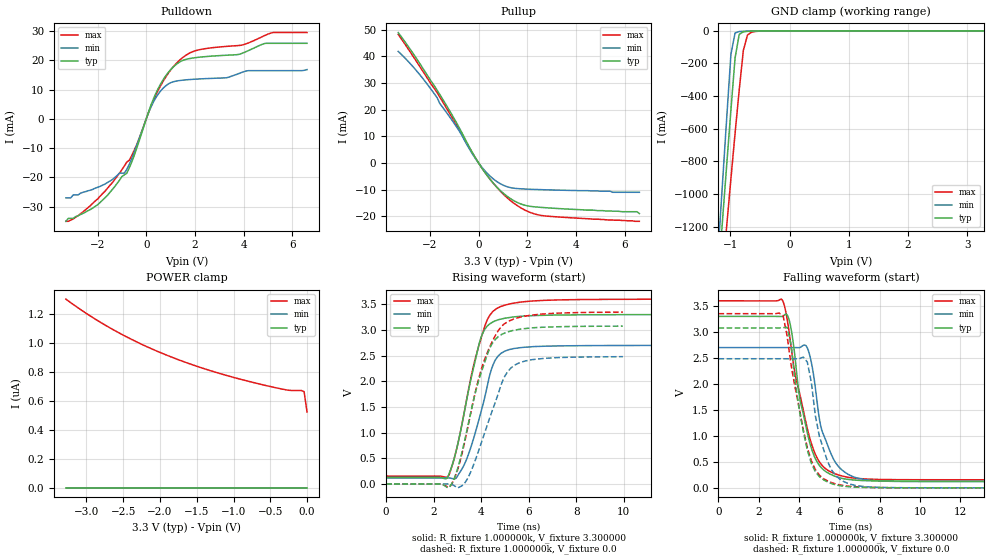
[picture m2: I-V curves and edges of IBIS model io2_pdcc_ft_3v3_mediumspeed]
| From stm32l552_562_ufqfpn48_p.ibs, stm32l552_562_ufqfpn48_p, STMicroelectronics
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|   Model io2_pdcc_ft_3v3_mediumspeed
[Model]  io2_pdcc_ft_3v3_mediumspeed
Model_type I/O
Polarity   Non-Inverting
Enable   Active-Low
Vinl =   0.990000V
Vinh =   2.310000V
Vmeas =  1.650000V
Cref =   40.000000pF
Rref =   100.000000M
Vref =   0.0V
C_comp   4.843300pF   4.282700pF   5.299100pF
[Temperature Range]   25.000000   -40.000000   0.125000k
[Pullup Reference]   3.300000V   2.700000V   3.600000V
[Pulldown Reference]   0.0V   0.0V   0.0V
[POWER Clamp Reference]   3.300000V   2.700000V   3.600000V
[GND Clamp Reference]   0.0V   0.0V   0.0V
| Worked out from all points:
|   slope of the pulldown table from 0 to 0.495 V, typ, clamps not added: 47.5 ohm
|   slope of the pullup table from 0 to 0.495 V, typ, clamps not added: 77.3 ohm
|   GND clamp passes 1 mA (typ) near -0.58 V on its own axis
|   rising waveform, R_fixture 1.000000k, V_fixture 3.300000: 20-80 % time 874ps typ, 892ps min, 997ps max; typ from 0.128 V to 3.3 V
|   rising waveform, R_fixture 1.000000k, V_fixture 0.0: 20-80 % time 1.03ns typ, 1.11ns min, 1.14ns max; typ from 0 V to 3.07 V
|   falling waveform, R_fixture 1.000000k, V_fixture 3.300000: 20-80 % time 859ps typ, 894ps min, 1.08ns max; typ from 3.3 V to 0.128 V
|   falling waveform, R_fixture 1.000000k, V_fixture 0.0: 20-80 % time 807ps typ, 805ps min, 998ps max; typ from 3.08 V to 0 V
[Pulldown]
|Voltage   I(typ)   I(min)   I(max)
-3.3V     -35mA      -27mA      -35mA
-2V       -29.4mA    -23.4mA    -27.4mA
-800mV    -18.58mA   -17.27mA   -14.77mA
-400mV    -10.26mA   -9.232mA   -8.958mA
100mV     2.513mA    2.208mA    2.267mA
400mV     8.782mA    7.287mA    8.184mA
800mV     14.68mA    11.26mA    14.27mA
1.3V      19.02mA    12.98mA    19.48mA
2V        20.86mA    13.52mA    23.19mA
3.9V      22.24mA    15.76mA    25.13mA
5.2V      25.78mA    16.44mA    29.44mA
6.6V      25.78mA    16.8mA     29.44mA
[Pullup]
|Voltage   I(typ)   I(min)   I(max)
-3.3V     48.98mA    41.91mA    48.31mA
-2.6V     39.91mA    35.19mA    38.84mA
-1.9V     30.08mA    27.03mA    29mA
-1.6V     25.82mA    22.46mA    24.9mA
-1.1V     18.19mA    16.17mA    17.21mA
100mV     -1.429mA   -1.206mA   -1.392mA
600mV     -7.545mA   -5.957mA   -7.567mA
1.2V      -12.7mA    -9.001mA   -13.28mA
1.8V      -15.6mA    -9.729mA   -17.2mA
2.5V      -16.63mA   -9.994mA   -19.58mA
6.5V      -18.3mA    -11mA      -21.9mA
6.6V      -19mA      -11mA      -21.9mA
[GND_clamp]
|Voltage   I(typ)   I(min)   I(max)
-3.3V     -9.767A    -9.748A    -9.881A
-1.2V     -1.489A    -1.316A    -1.768A
-1.13V    -1.15A     -919.7mA   -1.477A
-1.06V    -814.4mA   -527.2mA   -1.189A
-990mV    -484.1mA   -143.5mA   -905.3mA
-920mV    -166.2mA   -12.77mA   -627.6mA
-850mV    -21.87mA   -4.511mA   -362mA
-780mV    -5.991mA   -2.83mA    -119.7mA
-710mV    -3.238mA   -1.563mA   -25.44mA
-640mV    -1.838mA   -627.8uA   -8.016mA
-290mV    -1.61uA    0A         -104.4uA
3.28V     0A         0A         431.1nA
[POWER_clamp]
|Voltage   I(typ)   I(min)   I(max)
-3.28V    0A         0A         1.304uA
-2.96V    0A         0A         1.191uA
-2.6V     0A         0A         1.083uA
-2.24V    0A         0A         989.7nA
-1.84V    0A         0A         902.9nA
-1.4V     0A         0A         823.6nA
-880mV    0A         0A         747.1nA
-320mV    0A         0A         680.5nA
-240mV    0A         0A         673.6nA
-80mV     0A         0A         672.6nA
-40mV     0A         0A         665.5nA
0V        0A         0A         524.5nA
[Ramp]
| variable   typ   min   max
dV/dt_r  1.96650/1.13813n   1.60704/1.18468n   2.14475/1.25257n
dV/dt_f  1.97245/1.31685n   1.61310/1.32520n   2.15078/1.32548n
R_load = 10.000000k
[Rising Waveform]
R_fixture= 1.000000k
V_fixture= 3.300000
V_fixture_min= 2.700000
V_fixture_max= 3.600000
|time   V(typ)   V(min)   V(max)
0s        127.8mV    118.3mV    154.8mV
2.613ns   154mV      118.6mV    149.2mV
2.943ns   634.3mV    111.9mV    634.4mV
3.273ns   1.353V     362.4mV    1.359V
3.604ns   2.11V      767.6mV    2.143V
3.964ns   2.807V     1.35V      2.785V
4.264ns   3.077V     1.92V      3.201V
4.655ns   3.185V     2.452V     3.415V
6.246ns   3.278V     2.675V     3.564V
14.95ns   3.298V     2.698V     3.598V
[Rising Waveform]
R_fixture= 1.000000k
V_fixture= 0.0
V_fixture_min= 0.0
V_fixture_max= 0.0
|time   V(typ)   V(min)   V(max)
0s        35.26nV    22.58nV    11.62uV
2.723ns   -21.66mV   -3.899mV   -29.15mV
3.063ns   385.8mV    -65.05mV   359.4mV
3.483ns   1.221V     156.6mV    1.202V
3.964ns   2.114V     742.1mV    2.163V
4.324ns   2.597V     1.237V     2.63V
4.965ns   2.932V     2.068V     3.112V
5.405ns   2.994V     2.312V     3.216V
6.166ns   3.04V      2.422V     3.288V
9.97ns    3.073V     2.478V     3.345V
[Falling Waveform]
R_fixture= 1.000000k
V_fixture= 3.300000
V_fixture_min= 2.700000
V_fixture_max= 3.600000
|time   V(typ)   V(min)   V(max)
0s        3.3V       2.7V       3.6V
3.123ns   3.298V     2.7V       3.63V
3.393ns   3.335V     2.7V       3.272V
3.784ns   2.553V     2.7V       2.221V
4.024ns   1.743V     2.7V       1.818V
4.414ns   1.044V     2.687V     1.127V
5.045ns   412.7mV    1.236V     477mV
5.405ns   292.7mV    827.2mV    341.8mV
7.177ns   139.9mV    163.9mV    174.4mV
14.95ns   128.3mV    118.8mV    155.5mV
[Falling Waveform]
R_fixture= 1.000000k
V_fixture= 0.0
V_fixture_min= 0.0
V_fixture_max= 0.0
|time   V(typ)   V(min)   V(max)
0s        3.078V     2.485V     3.352V
3.003ns   3.077V     2.485V     3.364V
3.203ns   3.084V     2.485V     3.316V
3.403ns   3.091V     2.485V     2.922V
4.204ns   1.091V     2.518V     1.118V
4.605ns   472.2mV    2.03V      520.5mV
5.005ns   215.8mV    989.6mV    245.2mV
5.405ns   114.1mV    511.4mV    134.1mV
6.607ns   17.73mV    63.73mV    26.08mV
99.7ns    6.467uV    6.352uV    20.66uV
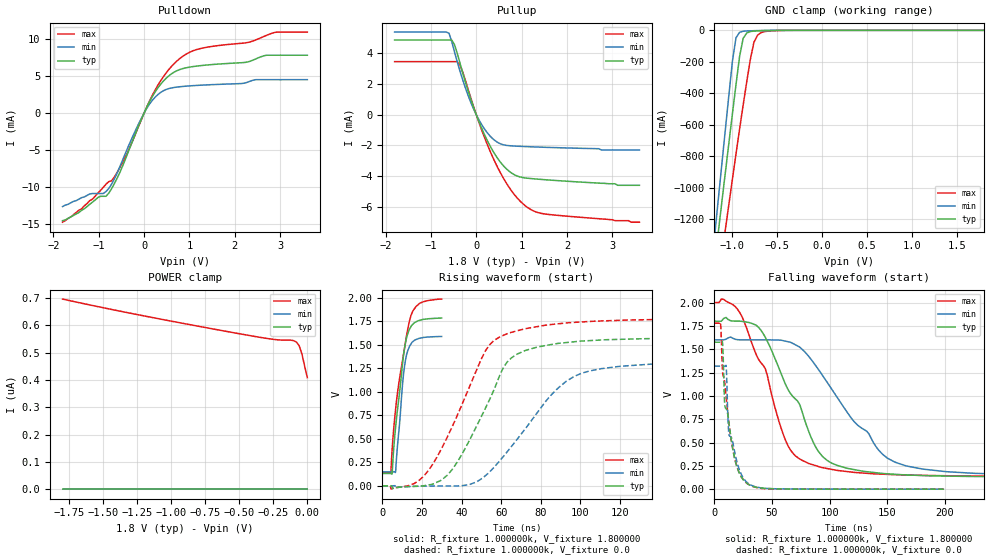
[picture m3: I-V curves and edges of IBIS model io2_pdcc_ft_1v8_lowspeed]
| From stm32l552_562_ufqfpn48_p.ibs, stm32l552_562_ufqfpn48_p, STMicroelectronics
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|   Model io2_pdcc_ft_1v8_lowspeed
[Model]  io2_pdcc_ft_1v8_lowspeed
Model_type I/O
Polarity   Non-Inverting
Enable   Active-Low
Vinl =   0.540000V
Vinh =   1.260000V
Vmeas =  0.900000V
Cref =   50.000000pF
Rref =   100.000000M
Vref =   0.0V
C_comp   4.366800pF   3.639100pF   5.105000pF
[Temperature Range]   25.000000   -40.000000   0.125000k
[Pullup Reference]   1.800000V   1.600000V   2.000000V
[Pulldown Reference]   0.0V   0.0V   0.0V
[POWER Clamp Reference]   1.800000V   1.600000V   2.000000V
[GND Clamp Reference]   0.0V   0.0V   0.0V
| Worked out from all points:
|   slope of the pulldown table from 0 to 0.27 V, typ, clamps not added: 87.5 ohm
|   slope of the pullup table from 0 to 0.27 V, typ, clamps not added: 147 ohm
|   GND clamp passes 1 mA (typ) near -0.58 V on its own axis
|   rising waveform, R_fixture 1.000000k, V_fixture 1.800000: 20-80 % time 5.14ns typ, 3.71ns min, 7.01ns max; typ from 0.131 V to 1.78 V
|   rising waveform, R_fixture 1.000000k, V_fixture 0.0: 20-80 % time 21.5ns typ, 30.3ns min, 22.8ns max; typ from 0 V to 1.57 V
|   falling waveform, R_fixture 1.000000k, V_fixture 1.800000: 20-80 % time 37ns typ, 52.6ns min, 31.5ns max; typ from 1.8 V to 0.131 V
|   falling waveform, R_fixture 1.000000k, V_fixture 0.0: 20-80 % time 9.82ns typ, 9.16ns min, 10.7ns max; typ from 1.57 V to 0 V
[Pulldown]
|Voltage   I(typ)   I(min)   I(max)
-1.8V     -14.5mA    -12.6mA    -14.7mA
-1.38V    -13.1mA    -11.4mA    -12.9mA
-900mV    -11.21mA   -10.84mA   -10mA
-780mV    -10.79mA   -10.16mA   -9.24mA
-480mV    -7.221mA   -6.409mA   -6.723mA
60mV      806.3uA    646.5uA    843.8uA
300mV     3.356mA    2.463mA    3.703mA
600mV     5.259mA    3.369mA    6.249mA
1.2V      6.348mA    3.729mA    8.613mA
2.28V     6.866mA    4.147mA    9.489mA
2.88V     7.779mA    4.489mA    10.85mA
3.6V      7.779mA    4.489mA    10.9mA
[Pullup]
|Voltage   I(typ)   I(min)   I(max)
-1.8V     4.843mA    5.363mA    3.44mA
-600mV    4.843mA    5.291mA    3.44mA
-540mV    4.843mA    4.745mA    3.44mA
-420mV    4.004mA    3.449mA    3.44mA
-300mV    2.736mA    2.275mA    2.784mA
-120mV    1.005mA    795.6uA    1.088mA
180mV     -1.289mA   -926.4uA   -1.468mA
480mV     -2.883mA   -1.823mA   -3.482mA
840mV     -3.912mA   -2.048mA   -5.199mA
1.14V     -4.143mA   -2.089mA   -6.059mA
1.44V     -4.22mA    -2.122mA   -6.431mA
3.6V      -4.6mA     -2.3mA     -7mA
[GND_clamp]
|Voltage   I(typ)   I(min)   I(max)
-1.8V     -4.43A     -4.747A    -4.297A
-1.2V     -1.489A    -1.316A    -1.768A
-1.16V    -1.295A    -1.089A    -1.601A
-1.12V    -1.102A    -863.2mA   -1.436A
-1.08V    -909.8mA   -638.7mA   -1.271A
-1V       -530.7mA   -197.2mA   -945.5mA
-960mV    -345.6mA   -47.17mA   -785.2mA
-920mV    -166mA     -12.66mA   -627.5mA
-880mV    -50.53mA   -5.875mA   -473.7mA
-760mV    -4.783mA   -2.396mA   -75.32mA
-680mV    -2.529mA   -1.097mA   -14.51mA
1.8V      0A         0A         305.1nA
[POWER_clamp]
|Voltage   I(typ)   I(min)   I(max)
-1.8V     0A         0A         696.8nA
-1.22V    0A         0A         637nA
-520mV    0A         0A         571.6nA
-260mV    0A         0A         549.8nA
-200mV    0A         0A         546.8nA
-120mV    0A         0A         546.1nA
-100mV    0A         0A         544.2nA
-80mV     0A         0A         539.2nA
-60mV     0A         0A         525.8nA
-40mV     0A         0A         495.9nA
-20mV     0A         0A         451.3nA
0V        0A         0A         408.6nA
[Ramp]
| variable   typ   min   max
dV/dt_r  1.06626/11.69097n   0.94386/12.69962n   1.18619/13.17653n
dV/dt_f  1.07230/25.60331n   0.95160/34.23696n   1.19173/22.45042n
R_load = 10.000000k
[Rising Waveform]
R_fixture= 1.000000k
V_fixture= 1.800000
V_fixture_min= 1.600000
V_fixture_max= 2.000000
|time   V(typ)   V(min)   V(max)
0s        131mV      148.5mV    138.1mV
4.264ns   131mV      148.5mV    139.8mV
4.985ns   142.4mV    148.6mV    398.4mV
6.667ns   619mV      147.5mV    811.3mV
9.91ns    1.245V     1.01V      1.3V
11.05ns   1.444V     1.252V     1.446V
12.37ns   1.588V     1.406V     1.618V
14.47ns   1.696V     1.51V      1.815V
18.86ns   1.761V     1.57V      1.942V
29.91ns   1.785V     1.589V     1.987V
[Rising Waveform]
R_fixture= 1.000000k
V_fixture= 0.0
V_fixture_min= 0.0
V_fixture_max= 0.0
|time   V(typ)   V(min)   V(max)
0s        30.16nV    26.35nV    13.38uV
18.42ns   -4.144mV   -4.632mV   55.4mV
25.23ns   15.91mV    -2.946mV   223mV
32.83ns   113.3mV    -2.022mV   520.3mV
52.05ns   826.4mV    107.9mV    1.437V
63.66ns   1.33V      378.3mV    1.624V
85.29ns   1.503V     967.4mV    1.716V
100.5ns   1.54V      1.197V     1.744V
135.3ns   1.566V     1.294V     1.768V
199.4ns   1.574V     1.316V     1.777V
[Falling Waveform]
R_fixture= 1.000000k
V_fixture= 1.800000
V_fixture_min= 1.600000
V_fixture_max= 2.000000
|time   V(typ)   V(min)   V(max)
0s        1.8V       1.6V       2V
20.02ns   1.8V       1.602V     1.928V
40.04ns   1.709V     1.6V       1.36V
66.07ns   1.024V     1.574V     419.2mV
74.07ns   906.4mV    1.522V     322.9mV
90.09ns   407mV      1.286V     243.6mV
106.1ns   256.9mV    992.5mV    201.9mV
150.2ns   164.7mV    332.3mV    158.5mV
202.2ns   140.2mV    186.8mV    143.8mV
997ns     131mV      148.5mV    138.1mV
[Falling Waveform]
R_fixture= 1.000000k
V_fixture= 0.0
V_fixture_min= 0.0
V_fixture_max= 0.0
|time   V(typ)   V(min)   V(max)
0s        1.575V     1.319V     1.778V
5.205ns   1.575V     1.319V     1.79V
6.807ns   1.587V     1.319V     1.301V
7.608ns   1.42V      1.319V     1.214V
8.809ns   925mV      1.319V     1.151V
10.01ns   864.1mV    1.327V     1.008V
12.41ns   724mV      598.6mV    726.9mV
18.82ns   265.8mV    327.6mV    271.9mV
28.43ns   61.73mV    71.22mV    59.55mV
199.4ns   19.37uV    39.34uV    31.94uV
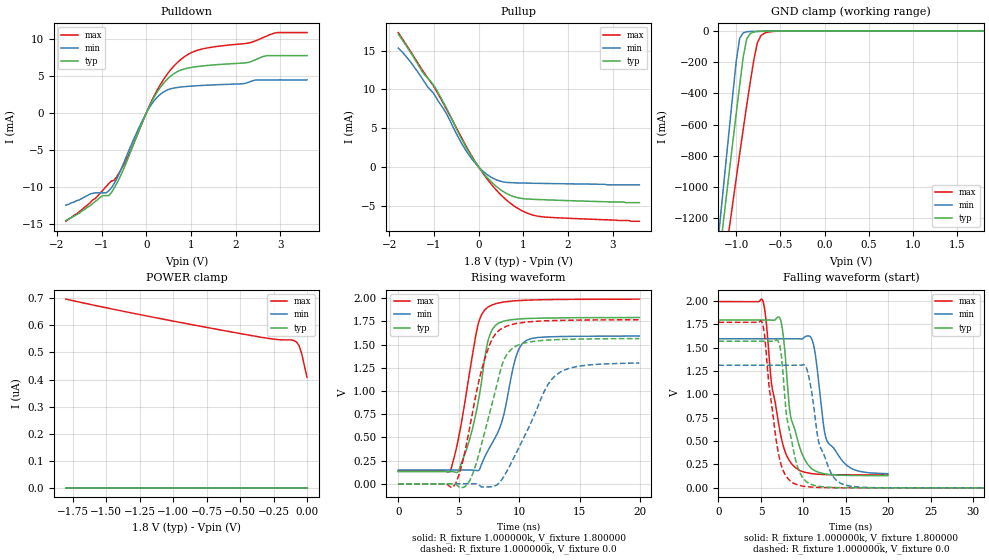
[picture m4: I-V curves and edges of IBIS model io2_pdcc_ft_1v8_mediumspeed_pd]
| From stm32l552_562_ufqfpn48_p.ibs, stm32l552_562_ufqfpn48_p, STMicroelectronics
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|   Model io2_pdcc_ft_1v8_mediumspeed_pd
[Model]  io2_pdcc_ft_1v8_mediumspeed_pd
Model_type I/O
Polarity   Non-Inverting
Enable   Active-Low
Vinl =   0.540000V
Vinh =   1.260000V
Vmeas =  0.900000V
Cref =   50.000000pF
Rref =   100.000000M
Vref =   0.0V
C_comp   4.367000pF   3.639100pF   5.105000pF
[Temperature Range]   25.000000   -40.000000   0.125000k
[Pullup Reference]   1.800000V   1.600000V   2.000000V
[Pulldown Reference]   0.0V   0.0V   0.0V
[POWER Clamp Reference]   1.800000V   1.600000V   2.000000V
[GND Clamp Reference]   0.0V   0.0V   0.0V
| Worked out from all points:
|   slope of the pulldown table from 0 to 0.27 V, typ, clamps not added: 87.5 ohm
|   slope of the pullup table from 0 to 0.27 V, typ, clamps not added: 147 ohm
|   GND clamp passes 1 mA (typ) near -0.58 V on its own axis
|   rising waveform, R_fixture 1.000000k, V_fixture 1.800000: 20-80 % time 1.42ns typ, 1.84ns min, 1.43ns max; typ from 0.131 V to 1.79 V
|   rising waveform, R_fixture 1.000000k, V_fixture 0.0: 20-80 % time 1.87ns typ, 2.78ns min, 1.8ns max; typ from 0 V to 1.56 V
|   falling waveform, R_fixture 1.000000k, V_fixture 1.800000: 20-80 % time 1.65ns typ, 1.82ns min, 1.69ns max; typ from 1.79 V to 0.131 V
|   falling waveform, R_fixture 1.000000k, V_fixture 0.0: 20-80 % time 1.47ns typ, 1.85ns min, 1.45ns max; typ from 1.57 V to 0 V
[Pulldown]
|Voltage   I(typ)   I(min)   I(max)
-1.8V     -14.6mA    -12.5mA    -14.7mA
-1.14V    -12mA      -10.84mA   -11.6mA
-900mV    -11.21mA   -10.84mA   -10mA
-780mV    -10.79mA   -10.16mA   -9.24mA
-480mV    -7.221mA   -6.409mA   -6.723mA
60mV      806.3uA    646.5uA    843.8uA
300mV     3.356mA    2.463mA    3.703mA
600mV     5.259mA    3.369mA    6.249mA
1.2V      6.348mA    3.729mA    8.613mA
2.28V     6.865mA    4.147mA    9.489mA
2.94V     7.795mA    4.497mA    10.92mA
3.6V      7.795mA    4.497mA    10.92mA
[Pullup]
|Voltage   I(typ)   I(min)   I(max)
-1.8V     17.13mA    15.32mA    17.31mA
-1.56V    15.08mA    13.79mA    15.21mA
-1.26V    12.28mA    11.37mA    12.49mA
-960mV    10.1mA     9.035mA    9.948mA
-720mV    7.587mA    6.866mA    7.447mA
-360mV    3.374mA    2.844mA    3.539mA
-120mV    1.005mA    795.6uA    1.089mA
180mV     -1.289mA   -926.4uA   -1.468mA
480mV     -2.883mA   -1.823mA   -3.482mA
900mV     -3.994mA   -2.057mA   -5.412mA
1.32V     -4.191mA   -2.109mA   -6.335mA
3.6V      -4.6mA     -2.3mA     -7mA
[GND_clamp]
|Voltage   I(typ)   I(min)   I(max)
-1.8V     -4.43A     -4.747A    -4.297A
-1.2V     -1.489A    -1.316A    -1.768A
-1.16V    -1.295A    -1.089A    -1.601A
-1.12V    -1.102A    -863.2mA   -1.436A
-1.08V    -909.9mA   -638.7mA   -1.271A
-1V       -530.7mA   -197.2mA   -945.5mA
-960mV    -345.6mA   -47.18mA   -785.2mA
-920mV    -166.1mA   -12.67mA   -627.5mA
-880mV    -50.55mA   -5.887mA   -473.7mA
-760mV    -4.794mA   -2.408mA   -75.33mA
-680mV    -2.54mA    -1.109mA   -14.52mA
1.8V      47.27uA    33.85uA    59.61uA
[POWER_clamp]
|Voltage   I(typ)   I(min)   I(max)
-1.8V     0A         0A         696.8nA
-1.22V    0A         0A         637nA
-540mV    0A         0A         573.4nA
-260mV    0A         0A         549.8nA
-200mV    0A         0A         546.8nA
-120mV    0A         0A         546.1nA
-100mV    0A         0A         544.2nA
-80mV     0A         0A         539.2nA
-60mV     0A         0A         525.8nA
-40mV     0A         0A         495.9nA
-20mV     0A         0A         451.3nA
0V        0A         0A         408.6nA
[Ramp]
| variable   typ   min   max
dV/dt_r  1.06272/1.80798n   0.94032/2.17420n   1.18169/1.75921n
dV/dt_f  1.06877/1.79550n   0.94819/1.80884n   1.18725/1.89525n
R_load = 10.000000k
[Rising Waveform]
R_fixture= 1.000000k
V_fixture= 1.800000
V_fixture_min= 1.600000
V_fixture_max= 2.000000
|time   V(typ)   V(min)   V(max)
0s        130.7mV    148.2mV    137.7mV
4.324ns   130.6mV    148.2mV    145.9mV
4.965ns   132.6mV    148.2mV    478.7mV
5.886ns   470.1mV    148mV      1.187V
6.687ns   932.9mV    148.2mV    1.756V
7.407ns   1.534V     354.3mV    1.903V
8.569ns   1.746V     667.8mV    1.956V
9.69ns    1.773V     1.35V      1.973V
10.33ns   1.779V     1.52V      1.978V
19.94ns   1.792V     1.593V     1.991V
[Rising Waveform]
R_fixture= 1.000000k
V_fixture= 0.0
V_fixture_min= 0.0
V_fixture_max= 0.0
|time   V(typ)   V(min)   V(max)
0s        29.98nV    26.18nV    13.16uV
4.685ns   -2.045mV   -5.99uV    -7.293mV
5.285ns   -41.21mV   -17.7uV    216.2mV
6.086ns   82.25mV    529.9uV    728.8mV
7.367ns   665mV      -33.63mV   1.431V
8.448ns   1.219V     25.07mV    1.665V
9.73ns    1.485V     326.4mV    1.728V
12.09ns   1.547V     1V         1.757V
13.01ns   1.553V     1.169V     1.76V
19.94ns   1.565V     1.302V     1.768V
[Falling Waveform]
R_fixture= 1.000000k
V_fixture= 1.800000
V_fixture_min= 1.600000
V_fixture_max= 2.000000
|time   V(typ)   V(min)   V(max)
0s        1.795V     1.595V     1.993V
5.205ns   1.795V     1.595V     2.005V
6.246ns   1.794V     1.595V     1.115V
7.327ns   1.793V     1.595V     564.8mV
8.408ns   815mV      1.595V     284mV
8.969ns   629.3mV    1.595V     224.3mV
11.01ns   203.1mV    1.586V     152.2mV
12.81ns   146mV      495.9mV    141.6mV
15.62ns   132.7mV    209mV      138.7mV
19.94ns   131.3mV    151.5mV    138.2mV
[Falling Waveform]
R_fixture= 1.000000k
V_fixture= 0.0
V_fixture_min= 0.0
V_fixture_max= 0.0
|time   V(typ)   V(min)   V(max)
0s        1.569V     1.312V     1.772V
5.205ns   1.569V     1.312V     1.759V
7.007ns   1.573V     1.312V     392.9mV
7.407ns   1.415V     1.312V     237mV
8.008ns   771.8mV    1.312V     119.5mV
9.81ns    123.4mV    1.312V     20.44mV
10.61ns   51.37mV    1.199V     10.53mV
12.01ns   13.85mV    428.8mV    4.006mV
15.42ns   1.254mV    19.71mV    750.2uV
99.7ns    40.65uV    47.69uV    50.34uV
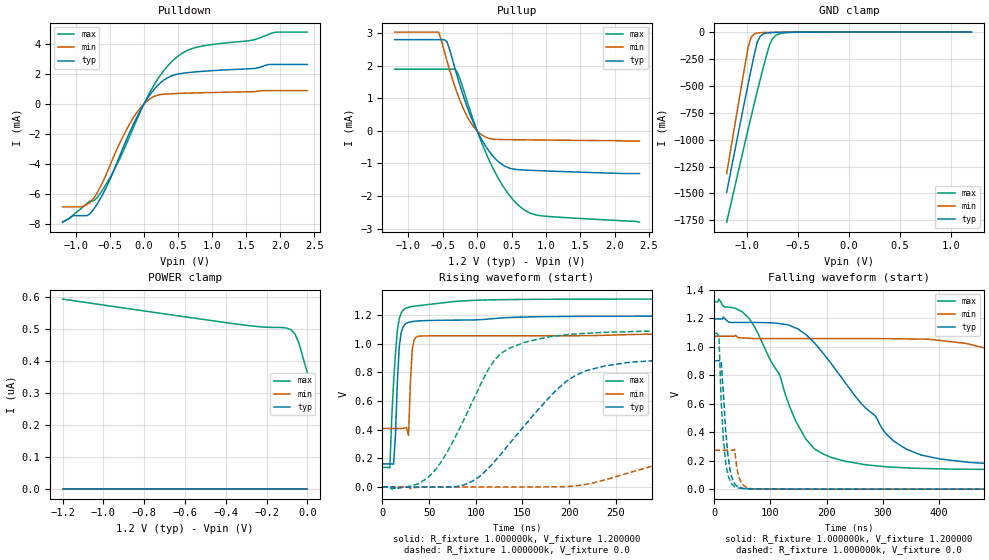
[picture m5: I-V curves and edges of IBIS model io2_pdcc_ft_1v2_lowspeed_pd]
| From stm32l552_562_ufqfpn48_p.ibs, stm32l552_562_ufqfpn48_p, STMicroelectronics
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|   Model io2_pdcc_ft_1v2_lowspeed_pd
[Model]  io2_pdcc_ft_1v2_lowspeed_pd
Model_type I/O
Polarity   Non-Inverting
Enable   Active-Low
Vinl =   0.360000V
Vinh =   0.840000V
Vmeas =  0.600000V
Cref =   30.000000pF
Rref =   100.000000M
Vref =   0.0V
C_comp   3.923200pF   3.103700pF   4.923200pF
[Temperature Range]   25.000000   -40.000000   0.125000k
[Pullup Reference]   1.200000V   1.080000V   1.320000V
[Pulldown Reference]   0.0V   0.0V   0.0V
[POWER Clamp Reference]   1.200000V   1.080000V   1.320000V
[GND Clamp Reference]   0.0V   0.0V   0.0V
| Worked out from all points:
|   slope of the pulldown table from 0 to 0.18 V, typ, clamps not added: 160 ohm
|   slope of the pullup table from 0 to 0.18 V, typ, clamps not added: 281 ohm
|   GND clamp passes 1 mA (typ) near -0.58 V on its own axis
|   rising waveform, R_fixture 1.000000k, V_fixture 1.200000: 20-80 % time 4.24ns typ, 2.84ns min, 6.45ns max; typ from 0.161 V to 1.19 V
|   rising waveform, R_fixture 1.000000k, V_fixture 0.0: 20-80 % time 73.4ns typ, 107ns min, 51.7ns max; typ from 0 V to 0.901 V
|   falling waveform, R_fixture 1.000000k, V_fixture 1.200000: 20-80 % time 125ns typ, 260ns min, 80.7ns max; typ from 1.19 V to 0.161 V
|   falling waveform, R_fixture 1.000000k, V_fixture 0.0: 20-80 % time 11ns typ, 9.08ns min, 9.43ns max; typ from 0.901 V to 0 V
[Pulldown]
|Voltage   I(typ)   I(min)   I(max)
-1.2V     -7.9mA     -6.879mA   -7.9mA
-920mV    -7.463mA   -6.879mA   -6.96mA
-720mV    -6.893mA   -6.163mA   -6.401mA
-440mV    -4.389mA   -3.449mA   -4.411mA
-120mV    -1.022mA   -674.6uA   -1.201mA
80mV      569.2uA    307.2uA    721.9uA
320mV     1.664mA    639.8uA    2.378mA
520mV     1.996mA    684uA      3.24mA
760mV     2.123mA    719uA      3.748mA
1.6V      2.341mA    798.9uA    4.245mA
1.92V     2.619mA    869.6uA    4.756mA
2.4V      2.619mA    869.6uA    4.773mA
[Pullup]
|Voltage   I(typ)   I(min)   I(max)
-1.2V     2.795mA    3.026mA    1.889mA
-560mV    2.795mA    3.026mA    1.889mA
-440mV    2.734mA    2.155mA    1.889mA
-320mV    1.896mA    1.332mA    1.889mA
-280mV    1.605mA    1.096mA    1.762mA
-160mV    820.1uA    504.5uA    1.006mA
0V        0A         0A         5nA
200mV     -697.7uA   -244.9uA   -1.014mA
400mV     -1.08mA    -267.8uA   -1.772mA
600mV     -1.19mA    -273.6uA   -2.279mA
840mV     -1.216mA   -279.5uA   -2.568mA
2.36V     -1.31mA    -310uA     -2.8mA
[GND_clamp]
|Voltage   I(typ)   I(min)   I(max)
-1.2V     -1.489A    -1.316A    -1.768A
-990mV    -483.9mA   -143.3mA   -905.1mA
-960mV    -345.5mA   -47.07mA   -785.1mA
-930mV    -210.2mA   -16.8mA    -666.5mA
-900mV    -91.91mA   -7.911mA   -550mA
-870mV    -37.66mA   -5.181mA   -436mA
-780mV    -5.842mA   -2.737mA   -119.5mA
-750mV    -4.316mA   -2.184mA   -59.88mA
-720mV    -3.389mA   -1.679mA   -31.04mA
-660mV    -2.131mA   -841.3uA   -10.47mA
-480mV    -203.8uA   -17.73uA   -1.431mA
1.2V      31.2uA     22.33uA    39.47uA
[POWER_clamp]
|Voltage   I(typ)   I(min)   I(max)
-1.2V     0A         0A         592.1nA
-600mV    0A         0A         536.8nA
-320mV    0A         0A         512.1nA
-220mV    0A         0A         505.2nA
-120mV    0A         0A         503.5nA
-100mV    0A         0A         501.6nA
-80mV     0A         0A         496.5nA
-60mV     0A         0A         482.9nA
-40mV     0A         0A         452.5nA
-20mV     0A         0A         407nA
0V        0A         0A         363nA
[Ramp]
| variable   typ   min   max
dV/dt_r  0.69876/29.11543n   0.60672/71.98953n   0.77363/26.42734n
dV/dt_f  0.70654/0.15396u   0.62605/0.23019u   0.77928/76.52655n
R_load = 10.000000k
[Rising Waveform]
R_fixture= 1.000000k
V_fixture= 1.200000
V_fixture_min= 1.080000
V_fixture_max= 1.320000
|time   V(typ)   V(min)   V(max)
0s        160.8mV    408.9mV    136.6mV
8.008ns   160.7mV    408.7mV    132.9mV
12.01ns   159mV      408.6mV    728.8mV
18.02ns   973.6mV    408.4mV    1.175V
22.02ns   1.117V     409.3mV    1.234V
28.03ns   1.151V     360.1mV    1.256V
30.03ns   1.154V     731.1mV    1.259V
32.03ns   1.156V     960.5mV    1.262V
44.04ns   1.162V     1.056V     1.271V
997ns     1.194V     1.073V     1.313V
[Rising Waveform]
R_fixture= 1.000000k
V_fixture= 0.0
V_fixture_min= 0.0
V_fixture_max= 0.0
|time   V(typ)   V(min)   V(max)
0s        35.3nV     40.11nV    16.5uV
48.05ns   -826.9uV   -946.6uV   60.88mV
68.07ns   -298.7uV   -388.4uV   229mV
96.1ns    38.86mV    -247.3uV   590.9mV
126.1ns   223.6mV    -447.3uV   928.7mV
176.2ns   607.4mV    365.2uV    1.047V
218.2ns   812.7mV    18.1mV     1.074V
302.3ns   887.3mV    164mV      1.09V
498.5ns   901.2mV    268.2mV    1.093V
997ns     901.5mV    272.9mV    1.093V
[Falling Waveform]
R_fixture= 1.000000k
V_fixture= 1.200000
V_fixture_min= 1.080000
V_fixture_max= 1.320000
|time   V(typ)   V(min)   V(max)
0s        1.194V     1.073V     1.313V
62.06ns   1.17V      1.059V     1.197V
116.1ns   1.162V     1.057V     802.5mV
162.2ns   1.087V     1.057V     357.9mV
208.2ns   881.1mV    1.057V     222.6mV
308.3ns   380.6mV    1.056V     156.4mV
368.4ns   239.7mV    1.053V     145.7mV
506.5ns   175.8mV    966.9mV    137.9mV
818.8ns   161.3mV    506.7mV    136.6mV
997ns     160.8mV    408.9mV    136.6mV
[Falling Waveform]
R_fixture= 1.000000k
V_fixture= 0.0
V_fixture_min= 0.0
V_fixture_max= 0.0
|time   V(typ)   V(min)   V(max)
0s        901.5mV    272.9mV    1.093V
8.008ns   901.5mV    272.9mV    1.076V
12.01ns   901.5mV    272.9mV    612.4mV
16.02ns   671.6mV    272.9mV    347.2mV
20.02ns   411.2mV    272.9mV    184.1mV
28.03ns   129.4mV    272.9mV    55.7mV
36.04ns   36.99mV    279.6mV    17.34mV
44.04ns   13.13mV    79.2mV     6.917mV
88.09ns   1.295mV    558.4uV    1.226mV
1.994us   35.3nV     40.11nV    16.5uV
